VERSION 5.7 ;
BUSBITCHARS "[]" ;
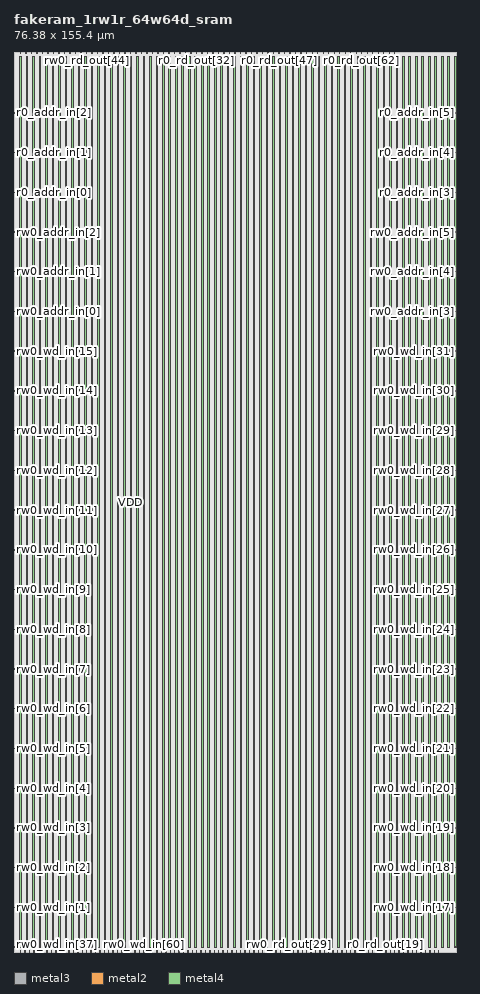
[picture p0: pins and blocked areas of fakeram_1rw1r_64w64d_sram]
MACRO fakeram_1rw1r_64w64d_sram
  FOREIGN fakeram_1rw1r_64w64d_sram 0 0 ;
  SYMMETRY X Y R90 ;
  SIZE 76.380 BY 155.400 ;
  CLASS BLOCK ;
  PIN rw0_wd_in[0]
    DIRECTION INPUT ;
    USE SIGNAL ;
    SHAPE ABUTMENT ;
    PORT
      LAYER metal3 ;
      RECT 0.000 0.805 0.210 0.875 ;
    END
  END rw0_wd_in[0]
  PIN rw0_wd_in[1]
    DIRECTION INPUT ;
    USE SIGNAL ;
    SHAPE ABUTMENT ;
    PORT
      LAYER metal3 ;
      RECT 0.000 7.665 0.210 7.735 ;
    END
  END rw0_wd_in[1]
  PIN rw0_wd_in[2]
    DIRECTION INPUT ;
    USE SIGNAL ;
    SHAPE ABUTMENT ;
    PORT
      LAYER metal3 ;
      RECT 0.000 14.525 0.210 14.595 ;
    END
  END rw0_wd_in[2]
  PIN rw0_wd_in[3]
    DIRECTION INPUT ;
    USE SIGNAL ;
    SHAPE ABUTMENT ;
    PORT
      LAYER metal3 ;
      RECT 0.000 21.385 0.210 21.455 ;
    END
  END rw0_wd_in[3]
  PIN rw0_wd_in[4]
    DIRECTION INPUT ;
    USE SIGNAL ;
    SHAPE ABUTMENT ;
    PORT
      LAYER metal3 ;
      RECT 0.000 28.245 0.210 28.315 ;
    END
  END rw0_wd_in[4]
  PIN rw0_wd_in[5]
    DIRECTION INPUT ;
    USE SIGNAL ;
    SHAPE ABUTMENT ;
    PORT
      LAYER metal3 ;
      RECT 0.000 35.105 0.210 35.175 ;
    END
  END rw0_wd_in[5]
  PIN rw0_wd_in[6]
    DIRECTION INPUT ;
    USE SIGNAL ;
    SHAPE ABUTMENT ;
    PORT
      LAYER metal3 ;
      RECT 0.000 41.965 0.210 42.035 ;
    END
  END rw0_wd_in[6]
  PIN rw0_wd_in[7]
    DIRECTION INPUT ;
    USE SIGNAL ;
    SHAPE ABUTMENT ;
    PORT
      LAYER metal3 ;
      RECT 0.000 48.825 0.210 48.895 ;
    END
  END rw0_wd_in[7]
  PIN rw0_wd_in[8]
    DIRECTION INPUT ;
    USE SIGNAL ;
    SHAPE ABUTMENT ;
    PORT
      LAYER metal3 ;
      RECT 0.000 55.685 0.210 55.755 ;
    END
  END rw0_wd_in[8]
  PIN rw0_wd_in[9]
    DIRECTION INPUT ;
    USE SIGNAL ;
    SHAPE ABUTMENT ;
    PORT
      LAYER metal3 ;
      RECT 0.000 62.545 0.210 62.615 ;
    END
  END rw0_wd_in[9]
  PIN rw0_wd_in[10]
    DIRECTION INPUT ;
    USE SIGNAL ;
    SHAPE ABUTMENT ;
    PORT
      LAYER metal3 ;
      RECT 0.000 69.405 0.210 69.475 ;
    END
  END rw0_wd_in[10]
  PIN rw0_wd_in[11]
    DIRECTION INPUT ;
    USE SIGNAL ;
    SHAPE ABUTMENT ;
    PORT
      LAYER metal3 ;
      RECT 0.000 76.265 0.210 76.335 ;
    END
  END rw0_wd_in[11]
  PIN rw0_wd_in[12]
    DIRECTION INPUT ;
    USE SIGNAL ;
    SHAPE ABUTMENT ;
    PORT
      LAYER metal3 ;
      RECT 0.000 83.125 0.210 83.195 ;
    END
  END rw0_wd_in[12]
  PIN rw0_wd_in[13]
    DIRECTION INPUT ;
    USE SIGNAL ;
    SHAPE ABUTMENT ;
    PORT
      LAYER metal3 ;
      RECT 0.000 89.985 0.210 90.055 ;
    END
  END rw0_wd_in[13]
  PIN rw0_wd_in[14]
    DIRECTION INPUT ;
    USE SIGNAL ;
    SHAPE ABUTMENT ;
    PORT
      LAYER metal3 ;
      RECT 0.000 96.845 0.210 96.915 ;
    END
  END rw0_wd_in[14]
  PIN rw0_wd_in[15]
    DIRECTION INPUT ;
    USE SIGNAL ;
    SHAPE ABUTMENT ;
    PORT
      LAYER metal3 ;
      RECT 0.000 103.705 0.210 103.775 ;
    END
  END rw0_wd_in[15]
  PIN rw0_wd_in[16]
    DIRECTION INPUT ;
    USE SIGNAL ;
    SHAPE ABUTMENT ;
    PORT
      LAYER metal3 ;
      RECT 76.170 0.805 76.380 0.875 ;
    END
  END rw0_wd_in[16]
  PIN rw0_wd_in[17]
    DIRECTION INPUT ;
    USE SIGNAL ;
    SHAPE ABUTMENT ;
    PORT
      LAYER metal3 ;
      RECT 76.170 7.665 76.380 7.735 ;
    END
  END rw0_wd_in[17]
  PIN rw0_wd_in[18]
    DIRECTION INPUT ;
    USE SIGNAL ;
    SHAPE ABUTMENT ;
    PORT
      LAYER metal3 ;
      RECT 76.170 14.525 76.380 14.595 ;
    END
  END rw0_wd_in[18]
  PIN rw0_wd_in[19]
    DIRECTION INPUT ;
    USE SIGNAL ;
    SHAPE ABUTMENT ;
    PORT
      LAYER metal3 ;
      RECT 76.170 21.385 76.380 21.455 ;
    END
  END rw0_wd_in[19]
  PIN rw0_wd_in[20]
    DIRECTION INPUT ;
    USE SIGNAL ;
    SHAPE ABUTMENT ;
    PORT
      LAYER metal3 ;
      RECT 76.170 28.245 76.380 28.315 ;
    END
  END rw0_wd_in[20]
  PIN rw0_wd_in[21]
    DIRECTION INPUT ;
    USE SIGNAL ;
    SHAPE ABUTMENT ;
    PORT
      LAYER metal3 ;
      RECT 76.170 35.105 76.380 35.175 ;
    END
  END rw0_wd_in[21]
  PIN rw0_wd_in[22]
    DIRECTION INPUT ;
    USE SIGNAL ;
    SHAPE ABUTMENT ;
    PORT
      LAYER metal3 ;
      RECT 76.170 41.965 76.380 42.035 ;
    END
  END rw0_wd_in[22]
  PIN rw0_wd_in[23]
    DIRECTION INPUT ;
    USE SIGNAL ;
    SHAPE ABUTMENT ;
    PORT
      LAYER metal3 ;
      RECT 76.170 48.825 76.380 48.895 ;
    END
  END rw0_wd_in[23]
  PIN rw0_wd_in[24]
    DIRECTION INPUT ;
    USE SIGNAL ;
    SHAPE ABUTMENT ;
    PORT
      LAYER metal3 ;
      RECT 76.170 55.685 76.380 55.755 ;
    END
  END rw0_wd_in[24]
  PIN rw0_wd_in[25]
    DIRECTION INPUT ;
    USE SIGNAL ;
    SHAPE ABUTMENT ;
    PORT
      LAYER metal3 ;
      RECT 76.170 62.545 76.380 62.615 ;
    END
  END rw0_wd_in[25]
  PIN rw0_wd_in[26]
    DIRECTION INPUT ;
    USE SIGNAL ;
    SHAPE ABUTMENT ;
    PORT
      LAYER metal3 ;
      RECT 76.170 69.405 76.380 69.475 ;
    END
  END rw0_wd_in[26]
  PIN rw0_wd_in[27]
    DIRECTION INPUT ;
    USE SIGNAL ;
    SHAPE ABUTMENT ;
    PORT
      LAYER metal3 ;
      RECT 76.170 76.265 76.380 76.335 ;
    END
  END rw0_wd_in[27]
  PIN rw0_wd_in[28]
    DIRECTION INPUT ;
    USE SIGNAL ;
    SHAPE ABUTMENT ;
    PORT
      LAYER metal3 ;
      RECT 76.170 83.125 76.380 83.195 ;
    END
  END rw0_wd_in[28]
  PIN rw0_wd_in[29]
    DIRECTION INPUT ;
    USE SIGNAL ;
    SHAPE ABUTMENT ;
    PORT
      LAYER metal3 ;
      RECT 76.170 89.985 76.380 90.055 ;
    END
  END rw0_wd_in[29]
  PIN rw0_wd_in[30]
    DIRECTION INPUT ;
    USE SIGNAL ;
    SHAPE ABUTMENT ;
    PORT
      LAYER metal3 ;
      RECT 76.170 96.845 76.380 96.915 ;
    END
  END rw0_wd_in[30]
  PIN rw0_wd_in[31]
    DIRECTION INPUT ;
    USE SIGNAL ;
    SHAPE ABUTMENT ;
    PORT
      LAYER metal3 ;
      RECT 76.170 103.705 76.380 103.775 ;
    END
  END rw0_wd_in[31]
  PIN rw0_wd_in[32]
    DIRECTION INPUT ;
    USE SIGNAL ;
    SHAPE ABUTMENT ;
    PORT
      LAYER metal2 ;
      RECT 1.105 0.000 1.175 0.210 ;
    END
  END rw0_wd_in[32]
  PIN rw0_wd_in[33]
    DIRECTION INPUT ;
    USE SIGNAL ;
    SHAPE ABUTMENT ;
    PORT
      LAYER metal2 ;
      RECT 1.865 0.000 1.935 0.210 ;
    END
  END rw0_wd_in[33]
  PIN rw0_wd_in[34]
    DIRECTION INPUT ;
    USE SIGNAL ;
    SHAPE ABUTMENT ;
    PORT
      LAYER metal2 ;
      RECT 2.625 0.000 2.695 0.210 ;
    END
  END rw0_wd_in[34]
  PIN rw0_wd_in[35]
    DIRECTION INPUT ;
    USE SIGNAL ;
    SHAPE ABUTMENT ;
    PORT
      LAYER metal2 ;
      RECT 3.385 0.000 3.455 0.210 ;
    END
  END rw0_wd_in[35]
  PIN rw0_wd_in[36]
    DIRECTION INPUT ;
    USE SIGNAL ;
    SHAPE ABUTMENT ;
    PORT
      LAYER metal2 ;
      RECT 4.145 0.000 4.215 0.210 ;
    END
  END rw0_wd_in[36]
  PIN rw0_wd_in[37]
    DIRECTION INPUT ;
    USE SIGNAL ;
    SHAPE ABUTMENT ;
    PORT
      LAYER metal2 ;
      RECT 4.905 0.000 4.975 0.210 ;
    END
  END rw0_wd_in[37]
  PIN rw0_wd_in[38]
    DIRECTION INPUT ;
    USE SIGNAL ;
    SHAPE ABUTMENT ;
    PORT
      LAYER metal2 ;
      RECT 5.665 0.000 5.735 0.210 ;
    END
  END rw0_wd_in[38]
  PIN rw0_wd_in[39]
    DIRECTION INPUT ;
    USE SIGNAL ;
    SHAPE ABUTMENT ;
    PORT
      LAYER metal2 ;
      RECT 6.425 0.000 6.495 0.210 ;
    END
  END rw0_wd_in[39]
  PIN rw0_wd_in[40]
    DIRECTION INPUT ;
    USE SIGNAL ;
    SHAPE ABUTMENT ;
    PORT
      LAYER metal2 ;
      RECT 7.185 0.000 7.255 0.210 ;
    END
  END rw0_wd_in[40]
  PIN rw0_wd_in[41]
    DIRECTION INPUT ;
    USE SIGNAL ;
    SHAPE ABUTMENT ;
    PORT
      LAYER metal2 ;
      RECT 7.945 0.000 8.015 0.210 ;
    END
  END rw0_wd_in[41]
  PIN rw0_wd_in[42]
    DIRECTION INPUT ;
    USE SIGNAL ;
    SHAPE ABUTMENT ;
    PORT
      LAYER metal2 ;
      RECT 8.705 0.000 8.775 0.210 ;
    END
  END rw0_wd_in[42]
  PIN rw0_wd_in[43]
    DIRECTION INPUT ;
    USE SIGNAL ;
    SHAPE ABUTMENT ;
    PORT
      LAYER metal2 ;
      RECT 9.465 0.000 9.535 0.210 ;
    END
  END rw0_wd_in[43]
  PIN rw0_wd_in[44]
    DIRECTION INPUT ;
    USE SIGNAL ;
    SHAPE ABUTMENT ;
    PORT
      LAYER metal2 ;
      RECT 10.225 0.000 10.295 0.210 ;
    END
  END rw0_wd_in[44]
  PIN rw0_wd_in[45]
    DIRECTION INPUT ;
    USE SIGNAL ;
    SHAPE ABUTMENT ;
    PORT
      LAYER metal2 ;
      RECT 10.985 0.000 11.055 0.210 ;
    END
  END rw0_wd_in[45]
  PIN rw0_wd_in[46]
    DIRECTION INPUT ;
    USE SIGNAL ;
    SHAPE ABUTMENT ;
    PORT
      LAYER metal2 ;
      RECT 11.745 0.000 11.815 0.210 ;
    END
  END rw0_wd_in[46]
  PIN rw0_wd_in[47]
    DIRECTION INPUT ;
    USE SIGNAL ;
    SHAPE ABUTMENT ;
    PORT
      LAYER metal2 ;
      RECT 12.505 0.000 12.575 0.210 ;
    END
  END rw0_wd_in[47]
  PIN rw0_wd_in[48]
    DIRECTION INPUT ;
    USE SIGNAL ;
    SHAPE ABUTMENT ;
    PORT
      LAYER metal2 ;
      RECT 13.265 0.000 13.335 0.210 ;
    END
  END rw0_wd_in[48]
  PIN rw0_wd_in[49]
    DIRECTION INPUT ;
    USE SIGNAL ;
    SHAPE ABUTMENT ;
    PORT
      LAYER metal2 ;
      RECT 14.025 0.000 14.095 0.210 ;
    END
  END rw0_wd_in[49]
  PIN rw0_wd_in[50]
    DIRECTION INPUT ;
    USE SIGNAL ;
    SHAPE ABUTMENT ;
    PORT
      LAYER metal2 ;
      RECT 14.785 0.000 14.855 0.210 ;
    END
  END rw0_wd_in[50]
  PIN rw0_wd_in[51]
    DIRECTION INPUT ;
    USE SIGNAL ;
    SHAPE ABUTMENT ;
    PORT
      LAYER metal2 ;
      RECT 15.545 0.000 15.615 0.210 ;
    END
  END rw0_wd_in[51]
  PIN rw0_wd_in[52]
    DIRECTION INPUT ;
    USE SIGNAL ;
    SHAPE ABUTMENT ;
    PORT
      LAYER metal2 ;
      RECT 16.305 0.000 16.375 0.210 ;
    END
  END rw0_wd_in[52]
  PIN rw0_wd_in[53]
    DIRECTION INPUT ;
    USE SIGNAL ;
    SHAPE ABUTMENT ;
    PORT
      LAYER metal2 ;
      RECT 17.065 0.000 17.135 0.210 ;
    END
  END rw0_wd_in[53]
  PIN rw0_wd_in[54]
    DIRECTION INPUT ;
    USE SIGNAL ;
    SHAPE ABUTMENT ;
    PORT
      LAYER metal2 ;
      RECT 17.825 0.000 17.895 0.210 ;
    END
  END rw0_wd_in[54]
  PIN rw0_wd_in[55]
    DIRECTION INPUT ;
    USE SIGNAL ;
    SHAPE ABUTMENT ;
    PORT
      LAYER metal2 ;
      RECT 18.585 0.000 18.655 0.210 ;
    END
  END rw0_wd_in[55]
  PIN rw0_wd_in[56]
    DIRECTION INPUT ;
    USE SIGNAL ;
    SHAPE ABUTMENT ;
    PORT
      LAYER metal2 ;
      RECT 19.345 0.000 19.415 0.210 ;
    END
  END rw0_wd_in[56]
  PIN rw0_wd_in[57]
    DIRECTION INPUT ;
    USE SIGNAL ;
    SHAPE ABUTMENT ;
    PORT
      LAYER metal2 ;
      RECT 20.105 0.000 20.175 0.210 ;
    END
  END rw0_wd_in[57]
  PIN rw0_wd_in[58]
    DIRECTION INPUT ;
    USE SIGNAL ;
    SHAPE ABUTMENT ;
    PORT
      LAYER metal2 ;
      RECT 20.865 0.000 20.935 0.210 ;
    END
  END rw0_wd_in[58]
  PIN rw0_wd_in[59]
    DIRECTION INPUT ;
    USE SIGNAL ;
    SHAPE ABUTMENT ;
    PORT
      LAYER metal2 ;
      RECT 21.625 0.000 21.695 0.210 ;
    END
  END rw0_wd_in[59]
  PIN rw0_wd_in[60]
    DIRECTION INPUT ;
    USE SIGNAL ;
    SHAPE ABUTMENT ;
    PORT
      LAYER metal2 ;
      RECT 22.385 0.000 22.455 0.210 ;
    END
  END rw0_wd_in[60]
  PIN rw0_wd_in[61]
    DIRECTION INPUT ;
    USE SIGNAL ;
    SHAPE ABUTMENT ;
    PORT
      LAYER metal2 ;
      RECT 23.145 0.000 23.215 0.210 ;
    END
  END rw0_wd_in[61]
  PIN rw0_wd_in[62]
    DIRECTION INPUT ;
    USE SIGNAL ;
    SHAPE ABUTMENT ;
    PORT
      LAYER metal2 ;
      RECT 23.905 0.000 23.975 0.210 ;
    END
  END rw0_wd_in[62]
  PIN rw0_wd_in[63]
    DIRECTION INPUT ;
    USE SIGNAL ;
    SHAPE ABUTMENT ;
    PORT
      LAYER metal2 ;
      RECT 24.665 0.000 24.735 0.210 ;
    END
  END rw0_wd_in[63]
  PIN rw0_rd_out[0]
    DIRECTION OUTPUT ;
    USE SIGNAL ;
    SHAPE ABUTMENT ;
    PORT
      LAYER metal2 ;
      RECT 25.425 0.000 25.495 0.210 ;
    END
  END rw0_rd_out[0]
  PIN rw0_rd_out[1]
    DIRECTION OUTPUT ;
    USE SIGNAL ;
    SHAPE ABUTMENT ;
    PORT
      LAYER metal2 ;
      RECT 26.185 0.000 26.255 0.210 ;
    END
  END rw0_rd_out[1]
  PIN rw0_rd_out[2]
    DIRECTION OUTPUT ;
    USE SIGNAL ;
    SHAPE ABUTMENT ;
    PORT
      LAYER metal2 ;
      RECT 26.945 0.000 27.015 0.210 ;
    END
  END rw0_rd_out[2]
  PIN rw0_rd_out[3]
    DIRECTION OUTPUT ;
    USE SIGNAL ;
    SHAPE ABUTMENT ;
    PORT
      LAYER metal2 ;
      RECT 27.705 0.000 27.775 0.210 ;
    END
  END rw0_rd_out[3]
  PIN rw0_rd_out[4]
    DIRECTION OUTPUT ;
    USE SIGNAL ;
    SHAPE ABUTMENT ;
    PORT
      LAYER metal2 ;
      RECT 28.465 0.000 28.535 0.210 ;
    END
  END rw0_rd_out[4]
  PIN rw0_rd_out[5]
    DIRECTION OUTPUT ;
    USE SIGNAL ;
    SHAPE ABUTMENT ;
    PORT
      LAYER metal2 ;
      RECT 29.225 0.000 29.295 0.210 ;
    END
  END rw0_rd_out[5]
  PIN rw0_rd_out[6]
    DIRECTION OUTPUT ;
    USE SIGNAL ;
    SHAPE ABUTMENT ;
    PORT
      LAYER metal2 ;
      RECT 29.985 0.000 30.055 0.210 ;
    END
  END rw0_rd_out[6]
  PIN rw0_rd_out[7]
    DIRECTION OUTPUT ;
    USE SIGNAL ;
    SHAPE ABUTMENT ;
    PORT
      LAYER metal2 ;
      RECT 30.745 0.000 30.815 0.210 ;
    END
  END rw0_rd_out[7]
  PIN rw0_rd_out[8]
    DIRECTION OUTPUT ;
    USE SIGNAL ;
    SHAPE ABUTMENT ;
    PORT
      LAYER metal2 ;
      RECT 31.505 0.000 31.575 0.210 ;
    END
  END rw0_rd_out[8]
  PIN rw0_rd_out[9]
    DIRECTION OUTPUT ;
    USE SIGNAL ;
    SHAPE ABUTMENT ;
    PORT
      LAYER metal2 ;
      RECT 32.265 0.000 32.335 0.210 ;
    END
  END rw0_rd_out[9]
  PIN rw0_rd_out[10]
    DIRECTION OUTPUT ;
    USE SIGNAL ;
    SHAPE ABUTMENT ;
    PORT
      LAYER metal2 ;
      RECT 33.025 0.000 33.095 0.210 ;
    END
  END rw0_rd_out[10]
  PIN rw0_rd_out[11]
    DIRECTION OUTPUT ;
    USE SIGNAL ;
    SHAPE ABUTMENT ;
    PORT
      LAYER metal2 ;
      RECT 33.785 0.000 33.855 0.210 ;
    END
  END rw0_rd_out[11]
  PIN rw0_rd_out[12]
    DIRECTION OUTPUT ;
    USE SIGNAL ;
    SHAPE ABUTMENT ;
    PORT
      LAYER metal2 ;
      RECT 34.545 0.000 34.615 0.210 ;
    END
  END rw0_rd_out[12]
  PIN rw0_rd_out[13]
    DIRECTION OUTPUT ;
    USE SIGNAL ;
    SHAPE ABUTMENT ;
    PORT
      LAYER metal2 ;
      RECT 35.305 0.000 35.375 0.210 ;
    END
  END rw0_rd_out[13]
  PIN rw0_rd_out[14]
    DIRECTION OUTPUT ;
    USE SIGNAL ;
    SHAPE ABUTMENT ;
    PORT
      LAYER metal2 ;
      RECT 36.065 0.000 36.135 0.210 ;
    END
  END rw0_rd_out[14]
  PIN rw0_rd_out[15]
    DIRECTION OUTPUT ;
    USE SIGNAL ;
    SHAPE ABUTMENT ;
    PORT
      LAYER metal2 ;
      RECT 36.825 0.000 36.895 0.210 ;
    END
  END rw0_rd_out[15]
  PIN rw0_rd_out[16]
    DIRECTION OUTPUT ;
    USE SIGNAL ;
    SHAPE ABUTMENT ;
    PORT
      LAYER metal2 ;
      RECT 37.585 0.000 37.655 0.210 ;
    END
  END rw0_rd_out[16]
  PIN rw0_rd_out[17]
    DIRECTION OUTPUT ;
    USE SIGNAL ;
    SHAPE ABUTMENT ;
    PORT
      LAYER metal2 ;
      RECT 38.345 0.000 38.415 0.210 ;
    END
  END rw0_rd_out[17]
  PIN rw0_rd_out[18]
    DIRECTION OUTPUT ;
    USE SIGNAL ;
    SHAPE ABUTMENT ;
    PORT
      LAYER metal2 ;
      RECT 39.105 0.000 39.175 0.210 ;
    END
  END rw0_rd_out[18]
  PIN rw0_rd_out[19]
    DIRECTION OUTPUT ;
    USE SIGNAL ;
    SHAPE ABUTMENT ;
    PORT
      LAYER metal2 ;
      RECT 39.865 0.000 39.935 0.210 ;
    END
  END rw0_rd_out[19]
  PIN rw0_rd_out[20]
    DIRECTION OUTPUT ;
    USE SIGNAL ;
    SHAPE ABUTMENT ;
    PORT
      LAYER metal2 ;
      RECT 40.625 0.000 40.695 0.210 ;
    END
  END rw0_rd_out[20]
  PIN rw0_rd_out[21]
    DIRECTION OUTPUT ;
    USE SIGNAL ;
    SHAPE ABUTMENT ;
    PORT
      LAYER metal2 ;
      RECT 41.385 0.000 41.455 0.210 ;
    END
  END rw0_rd_out[21]
  PIN rw0_rd_out[22]
    DIRECTION OUTPUT ;
    USE SIGNAL ;
    SHAPE ABUTMENT ;
    PORT
      LAYER metal2 ;
      RECT 42.145 0.000 42.215 0.210 ;
    END
  END rw0_rd_out[22]
  PIN rw0_rd_out[23]
    DIRECTION OUTPUT ;
    USE SIGNAL ;
    SHAPE ABUTMENT ;
    PORT
      LAYER metal2 ;
      RECT 42.905 0.000 42.975 0.210 ;
    END
  END rw0_rd_out[23]
  PIN rw0_rd_out[24]
    DIRECTION OUTPUT ;
    USE SIGNAL ;
    SHAPE ABUTMENT ;
    PORT
      LAYER metal2 ;
      RECT 43.665 0.000 43.735 0.210 ;
    END
  END rw0_rd_out[24]
  PIN rw0_rd_out[25]
    DIRECTION OUTPUT ;
    USE SIGNAL ;
    SHAPE ABUTMENT ;
    PORT
      LAYER metal2 ;
      RECT 44.425 0.000 44.495 0.210 ;
    END
  END rw0_rd_out[25]
  PIN rw0_rd_out[26]
    DIRECTION OUTPUT ;
    USE SIGNAL ;
    SHAPE ABUTMENT ;
    PORT
      LAYER metal2 ;
      RECT 45.185 0.000 45.255 0.210 ;
    END
  END rw0_rd_out[26]
  PIN rw0_rd_out[27]
    DIRECTION OUTPUT ;
    USE SIGNAL ;
    SHAPE ABUTMENT ;
    PORT
      LAYER metal2 ;
      RECT 45.945 0.000 46.015 0.210 ;
    END
  END rw0_rd_out[27]
  PIN rw0_rd_out[28]
    DIRECTION OUTPUT ;
    USE SIGNAL ;
    SHAPE ABUTMENT ;
    PORT
      LAYER metal2 ;
      RECT 46.705 0.000 46.775 0.210 ;
    END
  END rw0_rd_out[28]
  PIN rw0_rd_out[29]
    DIRECTION OUTPUT ;
    USE SIGNAL ;
    SHAPE ABUTMENT ;
    PORT
      LAYER metal2 ;
      RECT 47.465 0.000 47.535 0.210 ;
    END
  END rw0_rd_out[29]
  PIN rw0_rd_out[30]
    DIRECTION OUTPUT ;
    USE SIGNAL ;
    SHAPE ABUTMENT ;
    PORT
      LAYER metal2 ;
      RECT 48.225 0.000 48.295 0.210 ;
    END
  END rw0_rd_out[30]
  PIN rw0_rd_out[31]
    DIRECTION OUTPUT ;
    USE SIGNAL ;
    SHAPE ABUTMENT ;
    PORT
      LAYER metal2 ;
      RECT 48.985 0.000 49.055 0.210 ;
    END
  END rw0_rd_out[31]
  PIN rw0_rd_out[32]
    DIRECTION OUTPUT ;
    USE SIGNAL ;
    SHAPE ABUTMENT ;
    PORT
      LAYER metal2 ;
      RECT 1.105 155.190 1.175 155.400 ;
    END
  END rw0_rd_out[32]
  PIN rw0_rd_out[33]
    DIRECTION OUTPUT ;
    USE SIGNAL ;
    SHAPE ABUTMENT ;
    PORT
      LAYER metal2 ;
      RECT 2.055 155.190 2.125 155.400 ;
    END
  END rw0_rd_out[33]
  PIN rw0_rd_out[34]
    DIRECTION OUTPUT ;
    USE SIGNAL ;
    SHAPE ABUTMENT ;
    PORT
      LAYER metal2 ;
      RECT 3.005 155.190 3.075 155.400 ;
    END
  END rw0_rd_out[34]
  PIN rw0_rd_out[35]
    DIRECTION OUTPUT ;
    USE SIGNAL ;
    SHAPE ABUTMENT ;
    PORT
      LAYER metal2 ;
      RECT 3.955 155.190 4.025 155.400 ;
    END
  END rw0_rd_out[35]
  PIN rw0_rd_out[36]
    DIRECTION OUTPUT ;
    USE SIGNAL ;
    SHAPE ABUTMENT ;
    PORT
      LAYER metal2 ;
      RECT 4.905 155.190 4.975 155.400 ;
    END
  END rw0_rd_out[36]
  PIN rw0_rd_out[37]
    DIRECTION OUTPUT ;
    USE SIGNAL ;
    SHAPE ABUTMENT ;
    PORT
      LAYER metal2 ;
      RECT 5.855 155.190 5.925 155.400 ;
    END
  END rw0_rd_out[37]
  PIN rw0_rd_out[38]
    DIRECTION OUTPUT ;
    USE SIGNAL ;
    SHAPE ABUTMENT ;
    PORT
      LAYER metal2 ;
      RECT 6.805 155.190 6.875 155.400 ;
    END
  END rw0_rd_out[38]
  PIN rw0_rd_out[39]
    DIRECTION OUTPUT ;
    USE SIGNAL ;
    SHAPE ABUTMENT ;
    PORT
      LAYER metal2 ;
      RECT 7.755 155.190 7.825 155.400 ;
    END
  END rw0_rd_out[39]
  PIN rw0_rd_out[40]
    DIRECTION OUTPUT ;
    USE SIGNAL ;
    SHAPE ABUTMENT ;
    PORT
      LAYER metal2 ;
      RECT 8.705 155.190 8.775 155.400 ;
    END
  END rw0_rd_out[40]
  PIN rw0_rd_out[41]
    DIRECTION OUTPUT ;
    USE SIGNAL ;
    SHAPE ABUTMENT ;
    PORT
      LAYER metal2 ;
      RECT 9.655 155.190 9.725 155.400 ;
    END
  END rw0_rd_out[41]
  PIN rw0_rd_out[42]
    DIRECTION OUTPUT ;
    USE SIGNAL ;
    SHAPE ABUTMENT ;
    PORT
      LAYER metal2 ;
      RECT 10.605 155.190 10.675 155.400 ;
    END
  END rw0_rd_out[42]
  PIN rw0_rd_out[43]
    DIRECTION OUTPUT ;
    USE SIGNAL ;
    SHAPE ABUTMENT ;
    PORT
      LAYER metal2 ;
      RECT 11.555 155.190 11.625 155.400 ;
    END
  END rw0_rd_out[43]
  PIN rw0_rd_out[44]
    DIRECTION OUTPUT ;
    USE SIGNAL ;
    SHAPE ABUTMENT ;
    PORT
      LAYER metal2 ;
      RECT 12.505 155.190 12.575 155.400 ;
    END
  END rw0_rd_out[44]
  PIN rw0_rd_out[45]
    DIRECTION OUTPUT ;
    USE SIGNAL ;
    SHAPE ABUTMENT ;
    PORT
      LAYER metal2 ;
      RECT 13.455 155.190 13.525 155.400 ;
    END
  END rw0_rd_out[45]
  PIN rw0_rd_out[46]
    DIRECTION OUTPUT ;
    USE SIGNAL ;
    SHAPE ABUTMENT ;
    PORT
      LAYER metal2 ;
      RECT 14.405 155.190 14.475 155.400 ;
    END
  END rw0_rd_out[46]
  PIN rw0_rd_out[47]
    DIRECTION OUTPUT ;
    USE SIGNAL ;
    SHAPE ABUTMENT ;
    PORT
      LAYER metal2 ;
      RECT 15.355 155.190 15.425 155.400 ;
    END
  END rw0_rd_out[47]
  PIN rw0_rd_out[48]
    DIRECTION OUTPUT ;
    USE SIGNAL ;
    SHAPE ABUTMENT ;
    PORT
      LAYER metal2 ;
      RECT 16.305 155.190 16.375 155.400 ;
    END
  END rw0_rd_out[48]
  PIN rw0_rd_out[49]
    DIRECTION OUTPUT ;
    USE SIGNAL ;
    SHAPE ABUTMENT ;
    PORT
      LAYER metal2 ;
      RECT 17.255 155.190 17.325 155.400 ;
    END
  END rw0_rd_out[49]
  PIN rw0_rd_out[50]
    DIRECTION OUTPUT ;
    USE SIGNAL ;
    SHAPE ABUTMENT ;
    PORT
      LAYER metal2 ;
      RECT 18.205 155.190 18.275 155.400 ;
    END
  END rw0_rd_out[50]
  PIN rw0_rd_out[51]
    DIRECTION OUTPUT ;
    USE SIGNAL ;
    SHAPE ABUTMENT ;
    PORT
      LAYER metal2 ;
      RECT 19.155 155.190 19.225 155.400 ;
    END
  END rw0_rd_out[51]
  PIN rw0_rd_out[52]
    DIRECTION OUTPUT ;
    USE SIGNAL ;
    SHAPE ABUTMENT ;
    PORT
      LAYER metal2 ;
      RECT 20.105 155.190 20.175 155.400 ;
    END
  END rw0_rd_out[52]
  PIN rw0_rd_out[53]
    DIRECTION OUTPUT ;
    USE SIGNAL ;
    SHAPE ABUTMENT ;
    PORT
      LAYER metal2 ;
      RECT 21.055 155.190 21.125 155.400 ;
    END
  END rw0_rd_out[53]
  PIN rw0_rd_out[54]
    DIRECTION OUTPUT ;
    USE SIGNAL ;
    SHAPE ABUTMENT ;
    PORT
      LAYER metal2 ;
      RECT 22.005 155.190 22.075 155.400 ;
    END
  END rw0_rd_out[54]
  PIN rw0_rd_out[55]
    DIRECTION OUTPUT ;
    USE SIGNAL ;
    SHAPE ABUTMENT ;
    PORT
      LAYER metal2 ;
      RECT 22.955 155.190 23.025 155.400 ;
    END
  END rw0_rd_out[55]
  PIN rw0_rd_out[56]
    DIRECTION OUTPUT ;
    USE SIGNAL ;
    SHAPE ABUTMENT ;
    PORT
      LAYER metal2 ;
      RECT 23.905 155.190 23.975 155.400 ;
    END
  END rw0_rd_out[56]
  PIN rw0_rd_out[57]
    DIRECTION OUTPUT ;
    USE SIGNAL ;
    SHAPE ABUTMENT ;
    PORT
      LAYER metal2 ;
      RECT 24.855 155.190 24.925 155.400 ;
    END
  END rw0_rd_out[57]
  PIN rw0_rd_out[58]
    DIRECTION OUTPUT ;
    USE SIGNAL ;
    SHAPE ABUTMENT ;
    PORT
      LAYER metal2 ;
      RECT 25.805 155.190 25.875 155.400 ;
    END
  END rw0_rd_out[58]
  PIN rw0_rd_out[59]
    DIRECTION OUTPUT ;
    USE SIGNAL ;
    SHAPE ABUTMENT ;
    PORT
      LAYER metal2 ;
      RECT 26.755 155.190 26.825 155.400 ;
    END
  END rw0_rd_out[59]
  PIN rw0_rd_out[60]
    DIRECTION OUTPUT ;
    USE SIGNAL ;
    SHAPE ABUTMENT ;
    PORT
      LAYER metal2 ;
      RECT 27.705 155.190 27.775 155.400 ;
    END
  END rw0_rd_out[60]
  PIN rw0_rd_out[61]
    DIRECTION OUTPUT ;
    USE SIGNAL ;
    SHAPE ABUTMENT ;
    PORT
      LAYER metal2 ;
      RECT 28.655 155.190 28.725 155.400 ;
    END
  END rw0_rd_out[61]
  PIN rw0_rd_out[62]
    DIRECTION OUTPUT ;
    USE SIGNAL ;
    SHAPE ABUTMENT ;
    PORT
      LAYER metal2 ;
      RECT 29.605 155.190 29.675 155.400 ;
    END
  END rw0_rd_out[62]
  PIN rw0_rd_out[63]
    DIRECTION OUTPUT ;
    USE SIGNAL ;
    SHAPE ABUTMENT ;
    PORT
      LAYER metal2 ;
      RECT 30.555 155.190 30.625 155.400 ;
    END
  END rw0_rd_out[63]
  PIN r0_rd_out[0]
    DIRECTION OUTPUT ;
    USE SIGNAL ;
    SHAPE ABUTMENT ;
    PORT
      LAYER metal2 ;
      RECT 49.745 0.000 49.815 0.210 ;
    END
  END r0_rd_out[0]
  PIN r0_rd_out[1]
    DIRECTION OUTPUT ;
    USE SIGNAL ;
    SHAPE ABUTMENT ;
    PORT
      LAYER metal2 ;
      RECT 50.505 0.000 50.575 0.210 ;
    END
  END r0_rd_out[1]
  PIN r0_rd_out[2]
    DIRECTION OUTPUT ;
    USE SIGNAL ;
    SHAPE ABUTMENT ;
    PORT
      LAYER metal2 ;
      RECT 51.265 0.000 51.335 0.210 ;
    END
  END r0_rd_out[2]
  PIN r0_rd_out[3]
    DIRECTION OUTPUT ;
    USE SIGNAL ;
    SHAPE ABUTMENT ;
    PORT
      LAYER metal2 ;
      RECT 52.025 0.000 52.095 0.210 ;
    END
  END r0_rd_out[3]
  PIN r0_rd_out[4]
    DIRECTION OUTPUT ;
    USE SIGNAL ;
    SHAPE ABUTMENT ;
    PORT
      LAYER metal2 ;
      RECT 52.785 0.000 52.855 0.210 ;
    END
  END r0_rd_out[4]
  PIN r0_rd_out[5]
    DIRECTION OUTPUT ;
    USE SIGNAL ;
    SHAPE ABUTMENT ;
    PORT
      LAYER metal2 ;
      RECT 53.545 0.000 53.615 0.210 ;
    END
  END r0_rd_out[5]
  PIN r0_rd_out[6]
    DIRECTION OUTPUT ;
    USE SIGNAL ;
    SHAPE ABUTMENT ;
    PORT
      LAYER metal2 ;
      RECT 54.305 0.000 54.375 0.210 ;
    END
  END r0_rd_out[6]
  PIN r0_rd_out[7]
    DIRECTION OUTPUT ;
    USE SIGNAL ;
    SHAPE ABUTMENT ;
    PORT
      LAYER metal2 ;
      RECT 55.065 0.000 55.135 0.210 ;
    END
  END r0_rd_out[7]
  PIN r0_rd_out[8]
    DIRECTION OUTPUT ;
    USE SIGNAL ;
    SHAPE ABUTMENT ;
    PORT
      LAYER metal2 ;
      RECT 55.825 0.000 55.895 0.210 ;
    END
  END r0_rd_out[8]
  PIN r0_rd_out[9]
    DIRECTION OUTPUT ;
    USE SIGNAL ;
    SHAPE ABUTMENT ;
    PORT
      LAYER metal2 ;
      RECT 56.585 0.000 56.655 0.210 ;
    END
  END r0_rd_out[9]
  PIN r0_rd_out[10]
    DIRECTION OUTPUT ;
    USE SIGNAL ;
    SHAPE ABUTMENT ;
    PORT
      LAYER metal2 ;
      RECT 57.345 0.000 57.415 0.210 ;
    END
  END r0_rd_out[10]
  PIN r0_rd_out[11]
    DIRECTION OUTPUT ;
    USE SIGNAL ;
    SHAPE ABUTMENT ;
    PORT
      LAYER metal2 ;
      RECT 58.105 0.000 58.175 0.210 ;
    END
  END r0_rd_out[11]
  PIN r0_rd_out[12]
    DIRECTION OUTPUT ;
    USE SIGNAL ;
    SHAPE ABUTMENT ;
    PORT
      LAYER metal2 ;
      RECT 58.865 0.000 58.935 0.210 ;
    END
  END r0_rd_out[12]
  PIN r0_rd_out[13]
    DIRECTION OUTPUT ;
    USE SIGNAL ;
    SHAPE ABUTMENT ;
    PORT
      LAYER metal2 ;
      RECT 59.625 0.000 59.695 0.210 ;
    END
  END r0_rd_out[13]
  PIN r0_rd_out[14]
    DIRECTION OUTPUT ;
    USE SIGNAL ;
    SHAPE ABUTMENT ;
    PORT
      LAYER metal2 ;
      RECT 60.385 0.000 60.455 0.210 ;
    END
  END r0_rd_out[14]
  PIN r0_rd_out[15]
    DIRECTION OUTPUT ;
    USE SIGNAL ;
    SHAPE ABUTMENT ;
    PORT
      LAYER metal2 ;
      RECT 61.145 0.000 61.215 0.210 ;
    END
  END r0_rd_out[15]
  PIN r0_rd_out[16]
    DIRECTION OUTPUT ;
    USE SIGNAL ;
    SHAPE ABUTMENT ;
    PORT
      LAYER metal2 ;
      RECT 61.905 0.000 61.975 0.210 ;
    END
  END r0_rd_out[16]
  PIN r0_rd_out[17]
    DIRECTION OUTPUT ;
    USE SIGNAL ;
    SHAPE ABUTMENT ;
    PORT
      LAYER metal2 ;
      RECT 62.665 0.000 62.735 0.210 ;
    END
  END r0_rd_out[17]
  PIN r0_rd_out[18]
    DIRECTION OUTPUT ;
    USE SIGNAL ;
    SHAPE ABUTMENT ;
    PORT
      LAYER metal2 ;
      RECT 63.425 0.000 63.495 0.210 ;
    END
  END r0_rd_out[18]
  PIN r0_rd_out[19]
    DIRECTION OUTPUT ;
    USE SIGNAL ;
    SHAPE ABUTMENT ;
    PORT
      LAYER metal2 ;
      RECT 64.185 0.000 64.255 0.210 ;
    END
  END r0_rd_out[19]
  PIN r0_rd_out[20]
    DIRECTION OUTPUT ;
    USE SIGNAL ;
    SHAPE ABUTMENT ;
    PORT
      LAYER metal2 ;
      RECT 64.945 0.000 65.015 0.210 ;
    END
  END r0_rd_out[20]
  PIN r0_rd_out[21]
    DIRECTION OUTPUT ;
    USE SIGNAL ;
    SHAPE ABUTMENT ;
    PORT
      LAYER metal2 ;
      RECT 65.705 0.000 65.775 0.210 ;
    END
  END r0_rd_out[21]
  PIN r0_rd_out[22]
    DIRECTION OUTPUT ;
    USE SIGNAL ;
    SHAPE ABUTMENT ;
    PORT
      LAYER metal2 ;
      RECT 66.465 0.000 66.535 0.210 ;
    END
  END r0_rd_out[22]
  PIN r0_rd_out[23]
    DIRECTION OUTPUT ;
    USE SIGNAL ;
    SHAPE ABUTMENT ;
    PORT
      LAYER metal2 ;
      RECT 67.225 0.000 67.295 0.210 ;
    END
  END r0_rd_out[23]
  PIN r0_rd_out[24]
    DIRECTION OUTPUT ;
    USE SIGNAL ;
    SHAPE ABUTMENT ;
    PORT
      LAYER metal2 ;
      RECT 67.985 0.000 68.055 0.210 ;
    END
  END r0_rd_out[24]
  PIN r0_rd_out[25]
    DIRECTION OUTPUT ;
    USE SIGNAL ;
    SHAPE ABUTMENT ;
    PORT
      LAYER metal2 ;
      RECT 68.745 0.000 68.815 0.210 ;
    END
  END r0_rd_out[25]
  PIN r0_rd_out[26]
    DIRECTION OUTPUT ;
    USE SIGNAL ;
    SHAPE ABUTMENT ;
    PORT
      LAYER metal2 ;
      RECT 69.505 0.000 69.575 0.210 ;
    END
  END r0_rd_out[26]
  PIN r0_rd_out[27]
    DIRECTION OUTPUT ;
    USE SIGNAL ;
    SHAPE ABUTMENT ;
    PORT
      LAYER metal2 ;
      RECT 70.265 0.000 70.335 0.210 ;
    END
  END r0_rd_out[27]
  PIN r0_rd_out[28]
    DIRECTION OUTPUT ;
    USE SIGNAL ;
    SHAPE ABUTMENT ;
    PORT
      LAYER metal2 ;
      RECT 71.025 0.000 71.095 0.210 ;
    END
  END r0_rd_out[28]
  PIN r0_rd_out[29]
    DIRECTION OUTPUT ;
    USE SIGNAL ;
    SHAPE ABUTMENT ;
    PORT
      LAYER metal2 ;
      RECT 71.785 0.000 71.855 0.210 ;
    END
  END r0_rd_out[29]
  PIN r0_rd_out[30]
    DIRECTION OUTPUT ;
    USE SIGNAL ;
    SHAPE ABUTMENT ;
    PORT
      LAYER metal2 ;
      RECT 72.545 0.000 72.615 0.210 ;
    END
  END r0_rd_out[30]
  PIN r0_rd_out[31]
    DIRECTION OUTPUT ;
    USE SIGNAL ;
    SHAPE ABUTMENT ;
    PORT
      LAYER metal2 ;
      RECT 73.305 0.000 73.375 0.210 ;
    END
  END r0_rd_out[31]
  PIN r0_rd_out[32]
    DIRECTION OUTPUT ;
    USE SIGNAL ;
    SHAPE ABUTMENT ;
    PORT
      LAYER metal2 ;
      RECT 31.505 155.190 31.575 155.400 ;
    END
  END r0_rd_out[32]
  PIN r0_rd_out[33]
    DIRECTION OUTPUT ;
    USE SIGNAL ;
    SHAPE ABUTMENT ;
    PORT
      LAYER metal2 ;
      RECT 32.455 155.190 32.525 155.400 ;
    END
  END r0_rd_out[33]
  PIN r0_rd_out[34]
    DIRECTION OUTPUT ;
    USE SIGNAL ;
    SHAPE ABUTMENT ;
    PORT
      LAYER metal2 ;
      RECT 33.405 155.190 33.475 155.400 ;
    END
  END r0_rd_out[34]
  PIN r0_rd_out[35]
    DIRECTION OUTPUT ;
    USE SIGNAL ;
    SHAPE ABUTMENT ;
    PORT
      LAYER metal2 ;
      RECT 34.355 155.190 34.425 155.400 ;
    END
  END r0_rd_out[35]
  PIN r0_rd_out[36]
    DIRECTION OUTPUT ;
    USE SIGNAL ;
    SHAPE ABUTMENT ;
    PORT
      LAYER metal2 ;
      RECT 35.305 155.190 35.375 155.400 ;
    END
  END r0_rd_out[36]
  PIN r0_rd_out[37]
    DIRECTION OUTPUT ;
    USE SIGNAL ;
    SHAPE ABUTMENT ;
    PORT
      LAYER metal2 ;
      RECT 36.255 155.190 36.325 155.400 ;
    END
  END r0_rd_out[37]
  PIN r0_rd_out[38]
    DIRECTION OUTPUT ;
    USE SIGNAL ;
    SHAPE ABUTMENT ;
    PORT
      LAYER metal2 ;
      RECT 37.205 155.190 37.275 155.400 ;
    END
  END r0_rd_out[38]
  PIN r0_rd_out[39]
    DIRECTION OUTPUT ;
    USE SIGNAL ;
    SHAPE ABUTMENT ;
    PORT
      LAYER metal2 ;
      RECT 38.155 155.190 38.225 155.400 ;
    END
  END r0_rd_out[39]
  PIN r0_rd_out[40]
    DIRECTION OUTPUT ;
    USE SIGNAL ;
    SHAPE ABUTMENT ;
    PORT
      LAYER metal2 ;
      RECT 39.105 155.190 39.175 155.400 ;
    END
  END r0_rd_out[40]
  PIN r0_rd_out[41]
    DIRECTION OUTPUT ;
    USE SIGNAL ;
    SHAPE ABUTMENT ;
    PORT
      LAYER metal2 ;
      RECT 40.055 155.190 40.125 155.400 ;
    END
  END r0_rd_out[41]
  PIN r0_rd_out[42]
    DIRECTION OUTPUT ;
    USE SIGNAL ;
    SHAPE ABUTMENT ;
    PORT
      LAYER metal2 ;
      RECT 41.005 155.190 41.075 155.400 ;
    END
  END r0_rd_out[42]
  PIN r0_rd_out[43]
    DIRECTION OUTPUT ;
    USE SIGNAL ;
    SHAPE ABUTMENT ;
    PORT
      LAYER metal2 ;
      RECT 41.955 155.190 42.025 155.400 ;
    END
  END r0_rd_out[43]
  PIN r0_rd_out[44]
    DIRECTION OUTPUT ;
    USE SIGNAL ;
    SHAPE ABUTMENT ;
    PORT
      LAYER metal2 ;
      RECT 42.905 155.190 42.975 155.400 ;
    END
  END r0_rd_out[44]
  PIN r0_rd_out[45]
    DIRECTION OUTPUT ;
    USE SIGNAL ;
    SHAPE ABUTMENT ;
    PORT
      LAYER metal2 ;
      RECT 43.855 155.190 43.925 155.400 ;
    END
  END r0_rd_out[45]
  PIN r0_rd_out[46]
    DIRECTION OUTPUT ;
    USE SIGNAL ;
    SHAPE ABUTMENT ;
    PORT
      LAYER metal2 ;
      RECT 44.805 155.190 44.875 155.400 ;
    END
  END r0_rd_out[46]
  PIN r0_rd_out[47]
    DIRECTION OUTPUT ;
    USE SIGNAL ;
    SHAPE ABUTMENT ;
    PORT
      LAYER metal2 ;
      RECT 45.755 155.190 45.825 155.400 ;
    END
  END r0_rd_out[47]
  PIN r0_rd_out[48]
    DIRECTION OUTPUT ;
    USE SIGNAL ;
    SHAPE ABUTMENT ;
    PORT
      LAYER metal2 ;
      RECT 46.705 155.190 46.775 155.400 ;
    END
  END r0_rd_out[48]
  PIN r0_rd_out[49]
    DIRECTION OUTPUT ;
    USE SIGNAL ;
    SHAPE ABUTMENT ;
    PORT
      LAYER metal2 ;
      RECT 47.655 155.190 47.725 155.400 ;
    END
  END r0_rd_out[49]
  PIN r0_rd_out[50]
    DIRECTION OUTPUT ;
    USE SIGNAL ;
    SHAPE ABUTMENT ;
    PORT
      LAYER metal2 ;
      RECT 48.605 155.190 48.675 155.400 ;
    END
  END r0_rd_out[50]
  PIN r0_rd_out[51]
    DIRECTION OUTPUT ;
    USE SIGNAL ;
    SHAPE ABUTMENT ;
    PORT
      LAYER metal2 ;
      RECT 49.555 155.190 49.625 155.400 ;
    END
  END r0_rd_out[51]
  PIN r0_rd_out[52]
    DIRECTION OUTPUT ;
    USE SIGNAL ;
    SHAPE ABUTMENT ;
    PORT
      LAYER metal2 ;
      RECT 50.505 155.190 50.575 155.400 ;
    END
  END r0_rd_out[52]
  PIN r0_rd_out[53]
    DIRECTION OUTPUT ;
    USE SIGNAL ;
    SHAPE ABUTMENT ;
    PORT
      LAYER metal2 ;
      RECT 51.455 155.190 51.525 155.400 ;
    END
  END r0_rd_out[53]
  PIN r0_rd_out[54]
    DIRECTION OUTPUT ;
    USE SIGNAL ;
    SHAPE ABUTMENT ;
    PORT
      LAYER metal2 ;
      RECT 52.405 155.190 52.475 155.400 ;
    END
  END r0_rd_out[54]
  PIN r0_rd_out[55]
    DIRECTION OUTPUT ;
    USE SIGNAL ;
    SHAPE ABUTMENT ;
    PORT
      LAYER metal2 ;
      RECT 53.355 155.190 53.425 155.400 ;
    END
  END r0_rd_out[55]
  PIN r0_rd_out[56]
    DIRECTION OUTPUT ;
    USE SIGNAL ;
    SHAPE ABUTMENT ;
    PORT
      LAYER metal2 ;
      RECT 54.305 155.190 54.375 155.400 ;
    END
  END r0_rd_out[56]
  PIN r0_rd_out[57]
    DIRECTION OUTPUT ;
    USE SIGNAL ;
    SHAPE ABUTMENT ;
    PORT
      LAYER metal2 ;
      RECT 55.255 155.190 55.325 155.400 ;
    END
  END r0_rd_out[57]
  PIN r0_rd_out[58]
    DIRECTION OUTPUT ;
    USE SIGNAL ;
    SHAPE ABUTMENT ;
    PORT
      LAYER metal2 ;
      RECT 56.205 155.190 56.275 155.400 ;
    END
  END r0_rd_out[58]
  PIN r0_rd_out[59]
    DIRECTION OUTPUT ;
    USE SIGNAL ;
    SHAPE ABUTMENT ;
    PORT
      LAYER metal2 ;
      RECT 57.155 155.190 57.225 155.400 ;
    END
  END r0_rd_out[59]
  PIN r0_rd_out[60]
    DIRECTION OUTPUT ;
    USE SIGNAL ;
    SHAPE ABUTMENT ;
    PORT
      LAYER metal2 ;
      RECT 58.105 155.190 58.175 155.400 ;
    END
  END r0_rd_out[60]
  PIN r0_rd_out[61]
    DIRECTION OUTPUT ;
    USE SIGNAL ;
    SHAPE ABUTMENT ;
    PORT
      LAYER metal2 ;
      RECT 59.055 155.190 59.125 155.400 ;
    END
  END r0_rd_out[61]
  PIN r0_rd_out[62]
    DIRECTION OUTPUT ;
    USE SIGNAL ;
    SHAPE ABUTMENT ;
    PORT
      LAYER metal2 ;
      RECT 60.005 155.190 60.075 155.400 ;
    END
  END r0_rd_out[62]
  PIN r0_rd_out[63]
    DIRECTION OUTPUT ;
    USE SIGNAL ;
    SHAPE ABUTMENT ;
    PORT
      LAYER metal2 ;
      RECT 60.955 155.190 61.025 155.400 ;
    END
  END r0_rd_out[63]
  PIN rw0_addr_in[0]
    DIRECTION INPUT ;
    USE SIGNAL ;
    SHAPE ABUTMENT ;
    PORT
      LAYER metal3 ;
      RECT 0.000 110.565 0.210 110.635 ;
    END
  END rw0_addr_in[0]
  PIN rw0_addr_in[1]
    DIRECTION INPUT ;
    USE SIGNAL ;
    SHAPE ABUTMENT ;
    PORT
      LAYER metal3 ;
      RECT 0.000 117.425 0.210 117.495 ;
    END
  END rw0_addr_in[1]
  PIN rw0_addr_in[2]
    DIRECTION INPUT ;
    USE SIGNAL ;
    SHAPE ABUTMENT ;
    PORT
      LAYER metal3 ;
      RECT 0.000 124.285 0.210 124.355 ;
    END
  END rw0_addr_in[2]
  PIN rw0_addr_in[3]
    DIRECTION INPUT ;
    USE SIGNAL ;
    SHAPE ABUTMENT ;
    PORT
      LAYER metal3 ;
      RECT 76.170 110.565 76.380 110.635 ;
    END
  END rw0_addr_in[3]
  PIN rw0_addr_in[4]
    DIRECTION INPUT ;
    USE SIGNAL ;
    SHAPE ABUTMENT ;
    PORT
      LAYER metal3 ;
      RECT 76.170 117.425 76.380 117.495 ;
    END
  END rw0_addr_in[4]
  PIN rw0_addr_in[5]
    DIRECTION INPUT ;
    USE SIGNAL ;
    SHAPE ABUTMENT ;
    PORT
      LAYER metal3 ;
      RECT 76.170 124.285 76.380 124.355 ;
    END
  END rw0_addr_in[5]
  PIN r0_addr_in[0]
    DIRECTION INPUT ;
    USE SIGNAL ;
    SHAPE ABUTMENT ;
    PORT
      LAYER metal3 ;
      RECT 0.000 131.145 0.210 131.215 ;
    END
  END r0_addr_in[0]
  PIN r0_addr_in[1]
    DIRECTION INPUT ;
    USE SIGNAL ;
    SHAPE ABUTMENT ;
    PORT
      LAYER metal3 ;
      RECT 0.000 138.005 0.210 138.075 ;
    END
  END r0_addr_in[1]
  PIN r0_addr_in[2]
    DIRECTION INPUT ;
    USE SIGNAL ;
    SHAPE ABUTMENT ;
    PORT
      LAYER metal3 ;
      RECT 0.000 144.865 0.210 144.935 ;
    END
  END r0_addr_in[2]
  PIN r0_addr_in[3]
    DIRECTION INPUT ;
    USE SIGNAL ;
    SHAPE ABUTMENT ;
    PORT
      LAYER metal3 ;
      RECT 76.170 131.145 76.380 131.215 ;
    END
  END r0_addr_in[3]
  PIN r0_addr_in[4]
    DIRECTION INPUT ;
    USE SIGNAL ;
    SHAPE ABUTMENT ;
    PORT
      LAYER metal3 ;
      RECT 76.170 138.005 76.380 138.075 ;
    END
  END r0_addr_in[4]
  PIN r0_addr_in[5]
    DIRECTION INPUT ;
    USE SIGNAL ;
    SHAPE ABUTMENT ;
    PORT
      LAYER metal3 ;
      RECT 76.170 144.865 76.380 144.935 ;
    END
  END r0_addr_in[5]
  PIN rw0_we_in
    DIRECTION INPUT ;
    USE SIGNAL ;
    SHAPE ABUTMENT ;
    PORT
      LAYER metal2 ;
      RECT 61.905 155.190 61.975 155.400 ;
    END
  END rw0_we_in
  PIN rw0_ce_in
    DIRECTION INPUT ;
    USE SIGNAL ;
    SHAPE ABUTMENT ;
    PORT
      LAYER metal2 ;
      RECT 62.855 155.190 62.925 155.400 ;
    END
  END rw0_ce_in
  PIN rw0_clk
    DIRECTION INPUT ;
    USE SIGNAL ;
    SHAPE ABUTMENT ;
    PORT
      LAYER metal2 ;
      RECT 63.805 155.190 63.875 155.400 ;
    END
  END rw0_clk
  PIN r0_ce_in
    DIRECTION INPUT ;
    USE SIGNAL ;
    SHAPE ABUTMENT ;
    PORT
      LAYER metal2 ;
      RECT 64.755 155.190 64.825 155.400 ;
    END
  END r0_ce_in
  PIN r0_clk
    DIRECTION INPUT ;
    USE SIGNAL ;
    SHAPE ABUTMENT ;
    PORT
      LAYER metal2 ;
      RECT 65.705 155.190 65.775 155.400 ;
    END
  END r0_clk
  PIN VSS
    DIRECTION INOUT ;
    USE GROUND ;
    PORT
      LAYER metal4 ;
      RECT 1.000 0.840 1.280 154.560 ;
      RECT 3.240 0.840 3.520 154.560 ;
      RECT 5.480 0.840 5.760 154.560 ;
      RECT 7.720 0.840 8.000 154.560 ;
      RECT 9.960 0.840 10.240 154.560 ;
      RECT 12.200 0.840 12.480 154.560 ;
      RECT 14.440 0.840 14.720 154.560 ;
      RECT 16.680 0.840 16.960 154.560 ;
      RECT 18.920 0.840 19.200 154.560 ;
      RECT 21.160 0.840 21.440 154.560 ;
      RECT 23.400 0.840 23.680 154.560 ;
      RECT 25.640 0.840 25.920 154.560 ;
      RECT 27.880 0.840 28.160 154.560 ;
      RECT 30.120 0.840 30.400 154.560 ;
      RECT 32.360 0.840 32.640 154.560 ;
      RECT 34.600 0.840 34.880 154.560 ;
      RECT 36.840 0.840 37.120 154.560 ;
      RECT 39.080 0.840 39.360 154.560 ;
      RECT 41.320 0.840 41.600 154.560 ;
      RECT 43.560 0.840 43.840 154.560 ;
      RECT 45.800 0.840 46.080 154.560 ;
      RECT 48.040 0.840 48.320 154.560 ;
      RECT 50.280 0.840 50.560 154.560 ;
      RECT 52.520 0.840 52.800 154.560 ;
      RECT 54.760 0.840 55.040 154.560 ;
      RECT 57.000 0.840 57.280 154.560 ;
      RECT 59.240 0.840 59.520 154.560 ;
      RECT 61.480 0.840 61.760 154.560 ;
      RECT 63.720 0.840 64.000 154.560 ;
      RECT 65.960 0.840 66.240 154.560 ;
      RECT 68.200 0.840 68.480 154.560 ;
      RECT 70.440 0.840 70.720 154.560 ;
      RECT 72.680 0.840 72.960 154.560 ;
      RECT 74.920 0.840 75.200 154.560 ;
    END
  END VSS
  PIN VDD
    DIRECTION INOUT ;
    USE POWER ;
    PORT
      LAYER metal4 ;
      RECT 2.120 0.840 2.400 154.560 ;
      RECT 4.360 0.840 4.640 154.560 ;
      RECT 6.600 0.840 6.880 154.560 ;
      RECT 8.840 0.840 9.120 154.560 ;
      RECT 11.080 0.840 11.360 154.560 ;
      RECT 13.320 0.840 13.600 154.560 ;
      RECT 15.560 0.840 15.840 154.560 ;
      RECT 17.800 0.840 18.080 154.560 ;
      RECT 20.040 0.840 20.320 154.560 ;
      RECT 22.280 0.840 22.560 154.560 ;
      RECT 24.520 0.840 24.800 154.560 ;
      RECT 26.760 0.840 27.040 154.560 ;
      RECT 29.000 0.840 29.280 154.560 ;
      RECT 31.240 0.840 31.520 154.560 ;
      RECT 33.480 0.840 33.760 154.560 ;
      RECT 35.720 0.840 36.000 154.560 ;
      RECT 37.960 0.840 38.240 154.560 ;
      RECT 40.200 0.840 40.480 154.560 ;
      RECT 42.440 0.840 42.720 154.560 ;
      RECT 44.680 0.840 44.960 154.560 ;
      RECT 46.920 0.840 47.200 154.560 ;
      RECT 49.160 0.840 49.440 154.560 ;
      RECT 51.400 0.840 51.680 154.560 ;
      RECT 53.640 0.840 53.920 154.560 ;
      RECT 55.880 0.840 56.160 154.560 ;
      RECT 58.120 0.840 58.400 154.560 ;
      RECT 60.360 0.840 60.640 154.560 ;
      RECT 62.600 0.840 62.880 154.560 ;
      RECT 64.840 0.840 65.120 154.560 ;
      RECT 67.080 0.840 67.360 154.560 ;
      RECT 69.320 0.840 69.600 154.560 ;
      RECT 71.560 0.840 71.840 154.560 ;
      RECT 73.800 0.840 74.080 154.560 ;
      RECT 76.040 0.840 76.320 154.560 ;
    END
  END VDD
  OBS
    LAYER metal1 ;
    RECT 0 0 76.380 155.400 ;
    LAYER metal2 ;
    RECT 0 0 76.380 155.400 ;
    LAYER metal3 ;
    RECT 0 0 76.380 155.400 ;
    LAYER metal4 ;
    RECT 0 0 76.380 155.400 ;
    LAYER OVERLAP ;
    RECT 0 0 76.380 155.400 ;
  END
END fakeram_1rw1r_64w64d_sram

END LIBRARY
